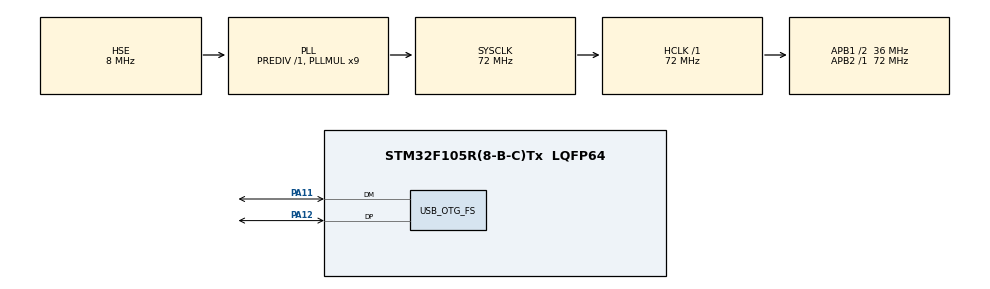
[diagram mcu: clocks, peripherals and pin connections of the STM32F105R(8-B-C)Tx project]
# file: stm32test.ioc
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Mcu.Family=STM32F1
Mcu.Name=STM32F105R(8-B-C)Tx
Mcu.Package=LQFP64
NVIC.OTG_FS_IRQn=true\:0\:0\:false\:false\:true\:false\:true
NVIC.PriorityGroup=NVIC_PRIORITYGROUP_4
NVIC.TIM1_UP_IRQn=true\:0\:0\:false\:false\:true\:false\:true
NVIC.TimeBase=TIM1_UP_IRQn
NVIC.TimeBaseIP=TIM1
PA11.Mode=Device_Only
PA11.Signal=USB_OTG_FS_DM
PA12.Mode=Device_Only
PA12.Signal=USB_OTG_FS_DP
PA13.Mode=Serial_Wire
PA13.Signal=SYS_JTMS-SWDIO
PA14.Mode=Serial_Wire
PA14.Signal=SYS_JTCK-SWCLK
PD0-OSC_IN.Mode=HSE-External-Oscillator
PD0-OSC_IN.Signal=RCC_OSC_IN
PD1-OSC_OUT.Mode=HSE-External-Oscillator
PD1-OSC_OUT.Signal=RCC_OSC_OUT
ProjectManager.HeapSize=0x200
ProjectManager.StackSize=0x400
ProjectManager.TargetToolchain=STM32CubeIDE
RCC.AHBFreq_Value=72000000
RCC.APB1CLKDivider=RCC_HCLK_DIV2
RCC.APB1Freq_Value=36000000
RCC.APB1TimFreq_Value=72000000
RCC.APB2Freq_Value=72000000
RCC.APB2TimFreq_Value=72000000
RCC.HCLKFreq_Value=72000000
RCC.PLLMUL=RCC_PLL_MUL9
RCC.SYSCLKFreq_VALUE=72000000
RCC.SYSCLKSource=RCC_SYSCLKSOURCE_PLLCLK
RCC.USBFreq_Value=48000000
USB_DEVICE.CLASS_NAME_FS=CDC
USB_DEVICE.VirtualMode=Cdc
USB_DEVICE.VirtualModeFS=Cdc_FS
USB_OTG_FS.VirtualMode=Device_Only
VP_SYS_VS_tim1.Mode=TIM1
VP_USB_DEVICE_VS_USB_DEVICE_CDC_FS.Mode=CDC_FS
board=custom

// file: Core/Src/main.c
/* USER CODE BEGIN Header */
/**
  ******************************************************************************
  * @file           : main.c
  * @brief          : Main program body
  ******************************************************************************
  * @attention
  *
  * <h2><center>&copy; Copyright (c) 2020 STMicroelectronics.
  * All rights reserved.</center></h2>
  *
  * This software component is licensed by ST under BSD 3-Clause license,
  * the "License"; You may not use this file except in compliance with the
  * License. You may obtain a copy of the License at:
  *                        opensource.org/licenses/BSD-3-Clause
  *
  ******************************************************************************
  */
/* USER CODE END Header */

#include "main.h"
#include "usb_device.h"
#include "usbd_cdc_if.h"

void SystemClock_Config(void);
static void MX_GPIO_Init(void);

int main(void)
{

  /* MCU Configuration--------------------------------------------------------*/

  /* Reset of all peripherals, Initializes the Flash interface and the Systick. */
  HAL_Init();

  /* Configure the system clock */
  SystemClock_Config();

  /* Initialize all configured peripherals */
  MX_GPIO_Init();
  MX_USB_DEVICE_Init();
  /* USER CODE BEGIN 2 */

  //HAL_GPIO_WritePin(GPIOC, GPIO_PIN_6, GPIO_PIN_SET);
  //HAL_GPIO_WritePin(GPIOC, GPIO_PIN_7, GPIO_PIN_SET);

  USBD_SendMidiMessages();
  /* USER CODE END 2 */

  /* Infinite loop */
  while (1)
  {
	  // get byte from receiver cable end write USB event for transmission

#if 0
	  __disable_irq();
	  if (USB_Tx_State==USB_TX_READY){
		  USBD_AddEvent( 0 );
		  USBD_MIDI_SendPacket();
		  //HAL_Delay(1);
	  }
	  __enable_irq();
#endif

	  if ( 1==get_flag_DataIn()) {
		  reset_flag_DataIn();
		  if (APP_Rx_length != 0)
		  {
		    USB_Tx_State = USB_TX_CONTINUE;
		  }
		  else
		  {
		    APP_Rx_ptr_out = 0;
		    APP_Rx_ptr_in = 0;
		    USB_Tx_State = USB_TX_READY;
		  }
	  }
	  if ( USB_Tx_State == USB_TX_READY ){
		    USBD_AddEvent( 0 );
		    USBD_MIDI_SendPacket();
	  }

#if 0
	  if (1 == MBX_B0){
		  // данные отправлены на хост успешно
		  MBX_B0 = 0;

		  if (APP_Rx_length != 0)
		  {
		    USB_Tx_State = USB_TX_CONTINUE;
		  }
		  else
		  {
		    APP_Rx_ptr_out = 0;
		    APP_Rx_ptr_in = 0;
		    USB_Tx_State = USB_TX_READY;
		  }

		  if ( USB_Tx_State == USB_TX_READY ){
			    USBD_AddEvent( 0 );
			    USBD_MIDI_SendPacket();
		  }

	  }
#endif

	  //HAL_Delay(1);
  }
}

void SystemClock_Config(void)
{
  RCC_OscInitTypeDef RCC_OscInitStruct = {0};
  RCC_ClkInitTypeDef RCC_ClkInitStruct = {0};
  RCC_PeriphCLKInitTypeDef PeriphClkInit = {0};

  /** Initializes the CPU, AHB and APB busses clocks
  */
  RCC_OscInitStruct.OscillatorType = RCC_OSCILLATORTYPE_HSE;
  RCC_OscInitStruct.HSEState = RCC_HSE_ON;
  RCC_OscInitStruct.HSEPredivValue = RCC_HSE_PREDIV_DIV1;
  RCC_OscInitStruct.HSIState = RCC_HSI_ON;
  RCC_OscInitStruct.Prediv1Source = RCC_PREDIV1_SOURCE_HSE;
  RCC_OscInitStruct.PLL.PLLState = RCC_PLL_ON;
  RCC_OscInitStruct.PLL.PLLSource = RCC_PLLSOURCE_HSE;
  RCC_OscInitStruct.PLL.PLLMUL = RCC_PLL_MUL9;
  RCC_OscInitStruct.PLL2.PLL2State = RCC_PLL_NONE;
  if (HAL_RCC_OscConfig(&RCC_OscInitStruct) != HAL_OK)
  {
    Error_Handler();
  }
  /** Initializes the CPU, AHB and APB busses clocks
  */
  RCC_ClkInitStruct.ClockType = RCC_CLOCKTYPE_HCLK|RCC_CLOCKTYPE_SYSCLK
                              |RCC_CLOCKTYPE_PCLK1|RCC_CLOCKTYPE_PCLK2;
  RCC_ClkInitStruct.SYSCLKSource = RCC_SYSCLKSOURCE_PLLCLK;
  RCC_ClkInitStruct.AHBCLKDivider = RCC_SYSCLK_DIV1;
  RCC_ClkInitStruct.APB1CLKDivider = RCC_HCLK_DIV2;
  RCC_ClkInitStruct.APB2CLKDivider = RCC_HCLK_DIV1;

  if (HAL_RCC_ClockConfig(&RCC_ClkInitStruct, FLASH_LATENCY_2) != HAL_OK)
  {
    Error_Handler();
  }
  PeriphClkInit.PeriphClockSelection = RCC_PERIPHCLK_USB;
  PeriphClkInit.UsbClockSelection = RCC_USBCLKSOURCE_PLL_DIV3;
  if (HAL_RCCEx_PeriphCLKConfig(&PeriphClkInit) != HAL_OK)
  {
    Error_Handler();
  }
  /** Configure the Systick interrupt time
  */
  __HAL_RCC_PLLI2S_ENABLE();
}

static void MX_GPIO_Init(void)
{

  /* GPIO Ports Clock Enable */
  __HAL_RCC_GPIOD_CLK_ENABLE();
  __HAL_RCC_GPIOA_CLK_ENABLE();
  __HAL_RCC_GPIOC_CLK_ENABLE();

  /*Configure GPIO pin Output Level */
  HAL_GPIO_WritePin(GPIOC, GPIO_PIN_6|GPIO_PIN_7, GPIO_PIN_RESET);

  GPIO_InitTypeDef GPIO_InitStruct = {0};

  /*Configure GPIO pins : GPIO_PIN_6|GPIO_PIN_7 */
  GPIO_InitStruct.Pin = GPIO_PIN_6|GPIO_PIN_7;
  GPIO_InitStruct.Mode = GPIO_MODE_OUTPUT_PP;
  GPIO_InitStruct.Pull = GPIO_NOPULL;
  GPIO_InitStruct.Speed = GPIO_SPEED_FREQ_LOW;
  HAL_GPIO_Init(GPIOC, &GPIO_InitStruct);

}

 /**
  * @brief  Period elapsed callback in non blocking mode
  * @note   This function is called  when TIM1 interrupt took place, inside
  * HAL_TIM_IRQHandler(). It makes a direct call to HAL_IncTick() to increment
  * a global variable "uwTick" used as application time base.
  * @param  htim : TIM handle
  * @retval None
  */
void HAL_TIM_PeriodElapsedCallback(TIM_HandleTypeDef *htim)
{
  if (htim->Instance == TIM1) {
    HAL_IncTick();
  }
}

void Error_Handler(void)
{
}

/************************ (C) COPYRIGHT STMicroelectronics *****END OF FILE****/
